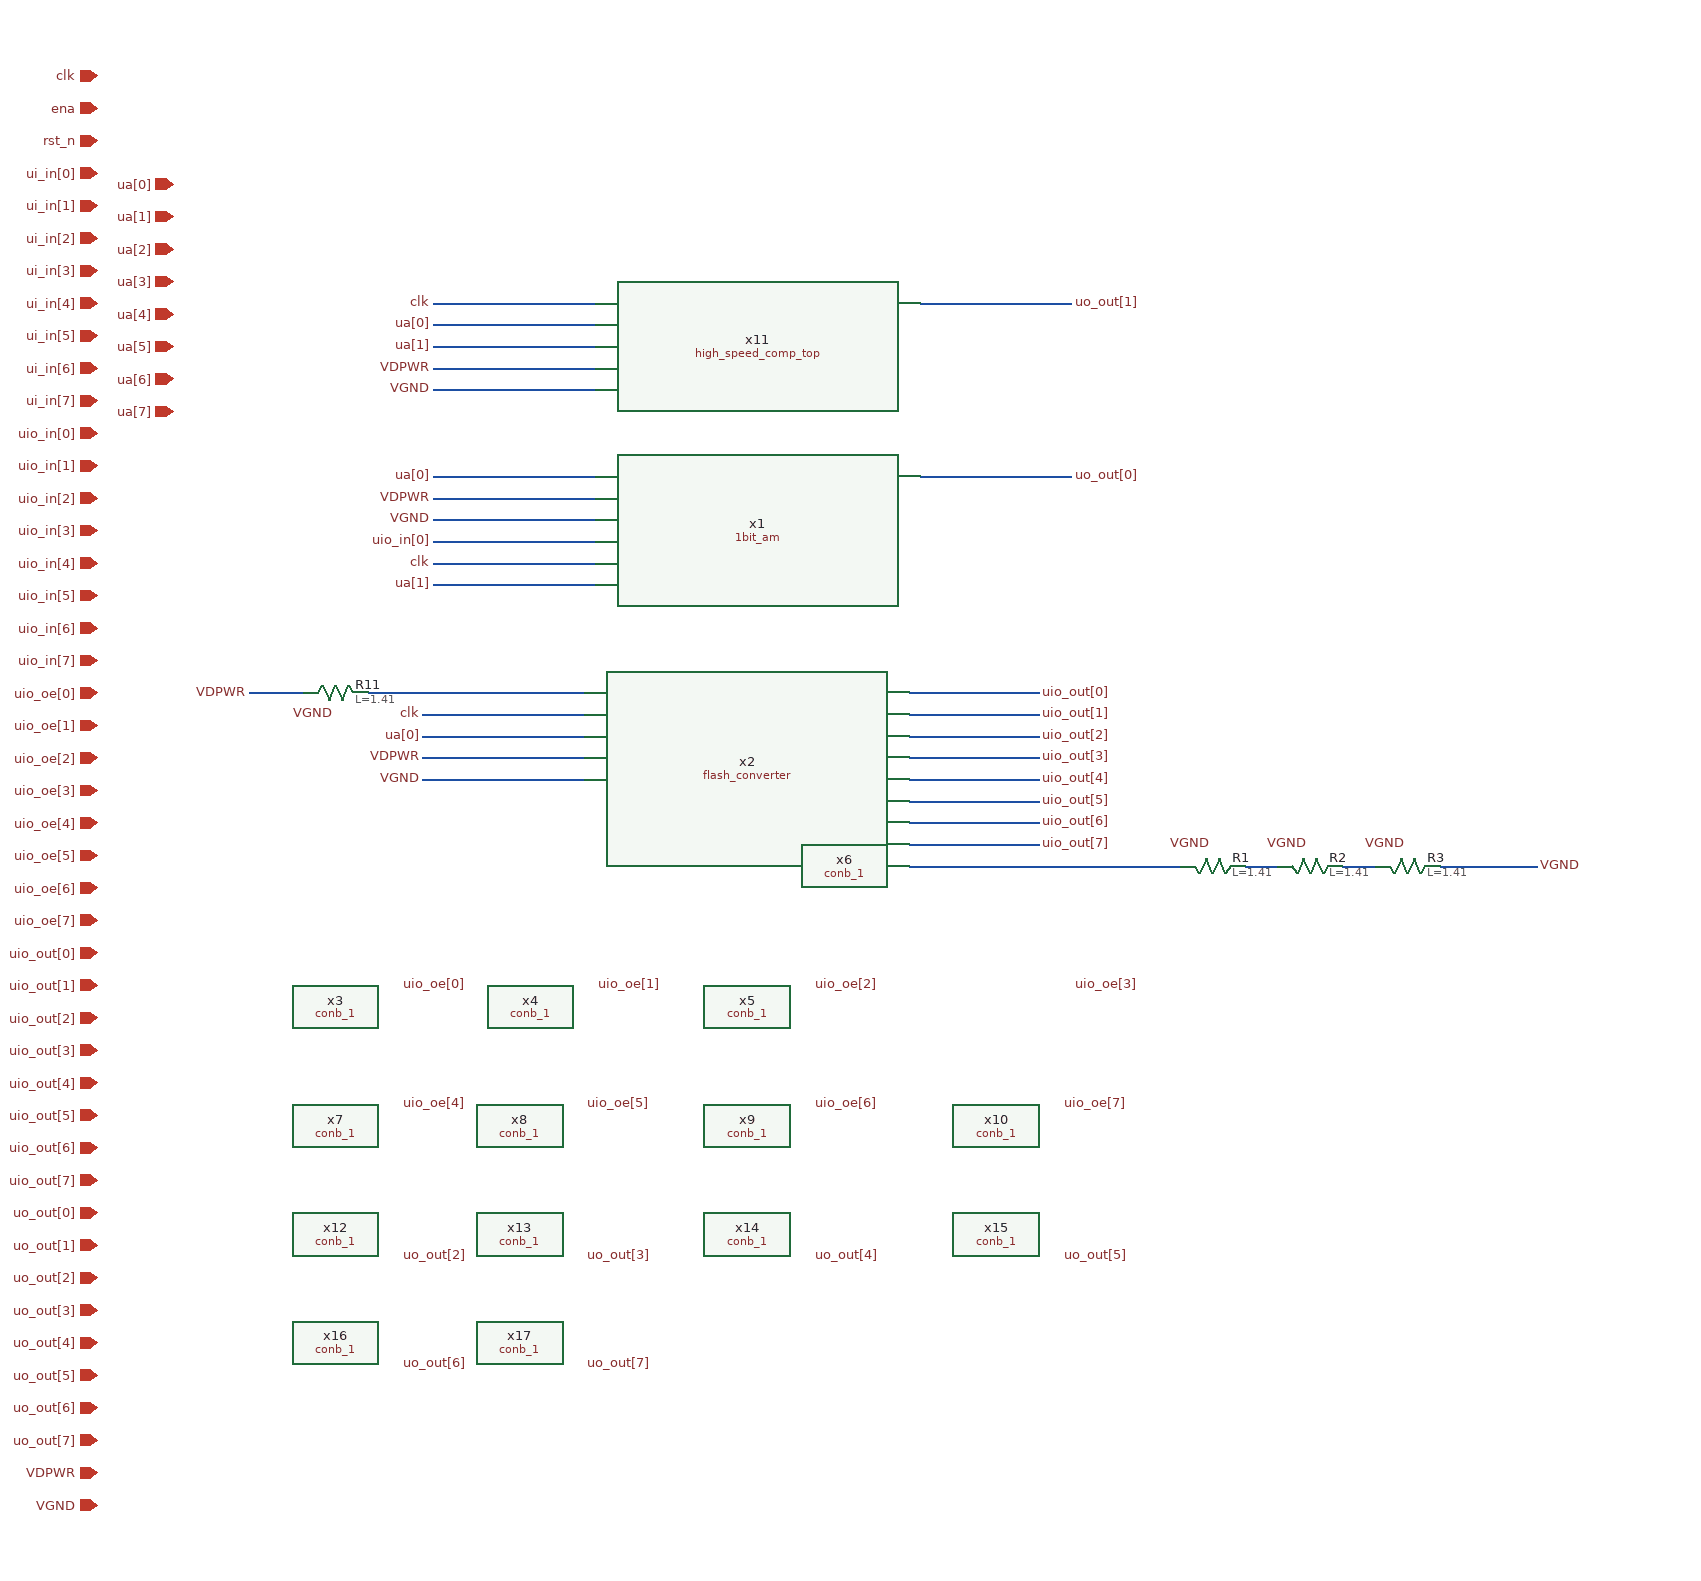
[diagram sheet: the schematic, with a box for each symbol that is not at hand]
v {xschem version=3.4.4 file_version=1.2
}
G {}
K {}
V {}
S {}
E {}
N 160 370 310 370 {
lab=clk}
N 150 510 300 510 {
lab=clk}
N 600 490 720 490 {
lab=uio_out[0]}
N 600 510 720 510 {
lab=uio_out[1]}
N 600 530 720 530 {
lab=uio_out[2]}
N 600 550 720 550 {
lab=uio_out[3]}
N 600 570 720 570 {
lab=uio_out[4]}
N 600 590 720 590 {
lab=uio_out[5]}
N 600 610 720 610 {
lab=uio_out[6]}
N 600 630 720 630 {
lab=uio_out[7]}
N 160 310 310 310 {
lab=VDPWR}
N 160 330 310 330 {
lab=VGND}
N 160 350 310 350 {
lab=uio_in[0]}
N 160 290 310 290 {
lab=ua[0]}
N 160 390 310 390 {
lab=ua[1]}
N 150 550 300 550 {
lab=VDPWR}
N 150 570 300 570 {
lab=VGND}
N 150 530 300 530 {
lab=ua[0]}
N 610 290 750 290 {
lab=uo_out[0]}
N 160 150 310 150 {
lab=ua[0]}
N 160 170 310 170 {
lab=ua[1]}
N 160 190 310 190 {
lab=VDPWR}
N 160 210 310 210 {
lab=VGND}
N 160 130 310 130 {
lab=clk}
N 610 130 750 130 {
lab=uo_out[1]}
N 600 650 850 650 {
lab=#net1}
N 910 650 940 650 {
lab=#net2}
N 1000 650 1030 650 {
lab=#net3}
N 1090 650 1180 650 {
lab=#net4}
N 100 490 300 490 {
lab=#net5}
N -10 490 40 490 {
lab=VDPWR}
C {ipin.sym} -150 -80 0 0 {name=p1 lab=clk}
C {ipin.sym} -150 -50 0 0 {name=p2 lab=ena}
C {ipin.sym} -150 -20 0 0 {name=p3 lab=rst_n}
C {ipin.sym} -80 20 0 0 {name=p4 lab=ua[0]}
C {ipin.sym} -80 50 0 0 {name=p5 lab=ua[1]}
C {ipin.sym} -80 80 0 0 {name=p6 lab=ua[2]}
C {ipin.sym} -80 110 0 0 {name=p7 lab=ua[3]}
C {ipin.sym} -80 140 0 0 {name=p8 lab=ua[4]}
C {ipin.sym} -80 170 0 0 {name=p9 lab=ua[5]}
C {ipin.sym} -80 200 0 0 {name=p10 lab=ua[6]}
C {ipin.sym} -80 230 0 0 {name=p11 lab=ua[7]}
C {ipin.sym} -150 10 0 0 {name=p12 lab=ui_in[0]}
C {ipin.sym} -150 40 0 0 {name=p13 lab=ui_in[1]}
C {ipin.sym} -150 70 0 0 {name=p14 lab=ui_in[2]}
C {ipin.sym} -150 100 0 0 {name=p15 lab=ui_in[3]}
C {ipin.sym} -150 130 0 0 {name=p16 lab=ui_in[4]}
C {ipin.sym} -150 160 0 0 {name=p17 lab=ui_in[5]}
C {ipin.sym} -150 190 0 0 {name=p18 lab=ui_in[6]}
C {ipin.sym} -150 220 0 0 {name=p19 lab=ui_in[7]}
C {ipin.sym} -150 250 0 0 {name=p20 lab=uio_in[0]}
C {ipin.sym} -150 280 0 0 {name=p21 lab=uio_in[1]}
C {ipin.sym} -150 310 0 0 {name=p22 lab=uio_in[2]}
C {ipin.sym} -150 340 0 0 {name=p23 lab=uio_in[3]}
C {ipin.sym} -150 370 0 0 {name=p24 lab=uio_in[4]}
C {ipin.sym} -150 400 0 0 {name=p25 lab=uio_in[5]}
C {ipin.sym} -150 430 0 0 {name=p26 lab=uio_in[6]}
C {ipin.sym} -150 460 0 0 {name=p27 lab=uio_in[7]}
C {ipin.sym} -150 490 0 0 {name=p28 lab=uio_oe[0]}
C {ipin.sym} -150 520 0 0 {name=p29 lab=uio_oe[1]}
C {ipin.sym} -150 550 0 0 {name=p30 lab=uio_oe[2]}
C {ipin.sym} -150 580 0 0 {name=p31 lab=uio_oe[3]}
C {ipin.sym} -150 610 0 0 {name=p32 lab=uio_oe[4]}
C {ipin.sym} -150 640 0 0 {name=p33 lab=uio_oe[5]}
C {ipin.sym} -150 670 0 0 {name=p34 lab=uio_oe[6]}
C {ipin.sym} -150 700 0 0 {name=p35 lab=uio_oe[7]}
C {ipin.sym} -150 730 0 0 {name=p36 lab=uio_out[0]}
C {ipin.sym} -150 760 0 0 {name=p37 lab=uio_out[1]}
C {ipin.sym} -150 790 0 0 {name=p38 lab=uio_out[2]}
C {ipin.sym} -150 820 0 0 {name=p39 lab=uio_out[3]}
C {ipin.sym} -150 850 0 0 {name=p40 lab=uio_out[4]}
C {ipin.sym} -150 880 0 0 {name=p41 lab=uio_out[5]}
C {ipin.sym} -150 910 0 0 {name=p42 lab=uio_out[6]}
C {ipin.sym} -150 940 0 0 {name=p43 lab=uio_out[7]}
C {ipin.sym} -150 970 0 0 {name=p44 lab=uo_out[0]}
C {ipin.sym} -150 1000 0 0 {name=p45 lab=uo_out[1]}
C {ipin.sym} -150 1030 0 0 {name=p46 lab=uo_out[2]}
C {ipin.sym} -150 1060 0 0 {name=p47 lab=uo_out[3]}
C {ipin.sym} -150 1090 0 0 {name=p48 lab=uo_out[4]}
C {ipin.sym} -150 1120 0 0 {name=p49 lab=uo_out[5]}
C {ipin.sym} -150 1150 0 0 {name=p50 lab=uo_out[6]}
C {ipin.sym} -150 1180 0 0 {name=p51 lab=uo_out[7]}
C {ipin.sym} -150 1210 0 0 {name=p52 lab=VDPWR}
C {ipin.sym} -150 1240 0 0 {name=p53 lab=VGND}
C {1bit_am.sym} 460 340 0 0 {name=x1}
C {flash_converter.sym} 450 570 0 0 {name=x2}
C {lab_pin.sym} 160 370 0 0 {name=p54 sig_type=std_logic lab=clk}
C {lab_pin.sym} 150 510 0 0 {name=p55 sig_type=std_logic lab=clk}
C {lab_pin.sym} 720 490 2 0 {name=p56 sig_type=std_logic lab=uio_out[0]}
C {lab_pin.sym} 720 510 2 0 {name=p57 sig_type=std_logic lab=uio_out[1]}
C {lab_pin.sym} 720 530 2 0 {name=p58 sig_type=std_logic lab=uio_out[2]}
C {lab_pin.sym} 720 550 2 0 {name=p59 sig_type=std_logic lab=uio_out[3]}
C {lab_pin.sym} 720 570 2 0 {name=p60 sig_type=std_logic lab=uio_out[4]}
C {lab_pin.sym} 720 590 2 0 {name=p61 sig_type=std_logic lab=uio_out[5]}
C {lab_pin.sym} 720 610 2 0 {name=p62 sig_type=std_logic lab=uio_out[6]}
C {lab_pin.sym} 720 630 2 0 {name=p63 sig_type=std_logic lab=uio_out[7]}
C {sky130_stdcells/conb_1.sym} 70 780 0 0 {name=x3 VGND=VGND VNB=VNB VPB=VPB VPWR=VPWR prefix=sky130_fd_sc_hd__ }
C {sky130_stdcells/conb_1.sym} 250 780 0 0 {name=x4 VGND=VGND VNB=VNB VPB=VPB VPWR=VPWR prefix=sky130_fd_sc_hd__ }
C {sky130_stdcells/conb_1.sym} 450 780 0 0 {name=x5 VGND=VGND VNB=VNB VPB=VPB VPWR=VPWR prefix=sky130_fd_sc_hd__ }
C {sky130_stdcells/conb_1.sym} 690 780 0 0 {name=x6 VGND=VGND VNB=VNB VPB=VPB VPWR=VPWR prefix=sky130_fd_sc_hd__ }
C {sky130_stdcells/conb_1.sym} 70 890 0 0 {name=x7 VGND=VGND VNB=VNB VPB=VPB VPWR=VPWR prefix=sky130_fd_sc_hd__ }
C {sky130_stdcells/conb_1.sym} 240 890 0 0 {name=x8 VGND=VGND VNB=VNB VPB=VPB VPWR=VPWR prefix=sky130_fd_sc_hd__ }
C {sky130_stdcells/conb_1.sym} 450 890 0 0 {name=x9 VGND=VGND VNB=VNB VPB=VPB VPWR=VPWR prefix=sky130_fd_sc_hd__ }
C {sky130_stdcells/conb_1.sym} 680 890 0 0 {name=x10 VGND=VGND VNB=VNB VPB=VPB VPWR=VPWR prefix=sky130_fd_sc_hd__ }
C {lab_pin.sym} 160 290 0 0 {name=p64 sig_type=std_logic lab=ua[0]}
C {lab_pin.sym} 160 310 0 0 {name=p65 sig_type=std_logic lab=VDPWR}
C {lab_pin.sym} 160 330 0 0 {name=p66 sig_type=std_logic lab=VGND}
C {lab_pin.sym} 130 760 2 0 {name=p67 sig_type=std_logic lab=uio_oe[0]}
C {lab_pin.sym} 310 760 2 0 {name=p68 sig_type=std_logic lab=uio_oe[1]}
C {lab_pin.sym} 510 760 2 0 {name=p69 sig_type=std_logic lab=uio_oe[2]}
C {lab_pin.sym} 750 760 2 0 {name=p70 sig_type=std_logic lab=uio_oe[3]}
C {lab_pin.sym} 130 870 2 0 {name=p71 sig_type=std_logic lab=uio_oe[4]}
C {lab_pin.sym} 300 870 2 0 {name=p72 sig_type=std_logic lab=uio_oe[5]}
C {lab_pin.sym} 510 870 2 0 {name=p73 sig_type=std_logic lab=uio_oe[6]}
C {lab_pin.sym} 740 870 2 0 {name=p74 sig_type=std_logic lab=uio_oe[7]}
C {lab_pin.sym} 160 390 0 0 {name=p75 sig_type=std_logic lab=ua[1]}
C {lab_pin.sym} 150 550 0 0 {name=p76 sig_type=std_logic lab=VDPWR}
C {lab_pin.sym} 150 570 0 0 {name=p77 sig_type=std_logic lab=VGND}
C {lab_pin.sym} 150 530 0 0 {name=p78 sig_type=std_logic lab=ua[0]}
C {lab_pin.sym} 750 290 2 0 {name=p79 sig_type=std_logic lab=uo_out[0]}
C {high_speed_comp_top.sym} 460 170 0 0 {name=x11}
C {lab_pin.sym} 160 350 0 0 {name=p80 sig_type=std_logic lab=uio_in[0]}
C {lab_pin.sym} 160 150 0 0 {name=p81 sig_type=std_logic lab=ua[0]}
C {lab_pin.sym} 160 170 0 0 {name=p82 sig_type=std_logic lab=ua[1]}
C {lab_pin.sym} 160 190 0 0 {name=p83 sig_type=std_logic lab=VDPWR}
C {lab_pin.sym} 160 210 0 0 {name=p84 sig_type=std_logic lab=VGND}
C {lab_pin.sym} 160 130 0 0 {name=p85 sig_type=std_logic lab=clk}
C {lab_pin.sym} 750 130 2 0 {name=p86 sig_type=std_logic lab=uo_out[1]}
C {sky130_stdcells/conb_1.sym} 70 990 0 0 {name=x12 VGND=VGND VNB=VNB VPB=VPB VPWR=VPWR prefix=sky130_fd_sc_hd__ }
C {sky130_stdcells/conb_1.sym} 240 990 0 0 {name=x13 VGND=VGND VNB=VNB VPB=VPB VPWR=VPWR prefix=sky130_fd_sc_hd__ }
C {sky130_stdcells/conb_1.sym} 450 990 0 0 {name=x14 VGND=VGND VNB=VNB VPB=VPB VPWR=VPWR prefix=sky130_fd_sc_hd__ }
C {sky130_stdcells/conb_1.sym} 680 990 0 0 {name=x15 VGND=VGND VNB=VNB VPB=VPB VPWR=VPWR prefix=sky130_fd_sc_hd__ }
C {lab_pin.sym} 130 1010 2 0 {name=p87 sig_type=std_logic lab=uo_out[2]}
C {lab_pin.sym} 300 1010 2 0 {name=p88 sig_type=std_logic lab=uo_out[3]}
C {lab_pin.sym} 510 1010 2 0 {name=p89 sig_type=std_logic lab=uo_out[4]}
C {lab_pin.sym} 740 1010 2 0 {name=p90 sig_type=std_logic lab=uo_out[5]}
C {sky130_stdcells/conb_1.sym} 70 1090 0 0 {name=x16 VGND=VGND VNB=VNB VPB=VPB VPWR=VPWR prefix=sky130_fd_sc_hd__ }
C {sky130_stdcells/conb_1.sym} 240 1090 0 0 {name=x17 VGND=VGND VNB=VNB VPB=VPB VPWR=VPWR prefix=sky130_fd_sc_hd__ }
C {lab_pin.sym} 130 1110 2 0 {name=p91 sig_type=std_logic lab=uo_out[6]}
C {lab_pin.sym} 300 1110 2 0 {name=p92 sig_type=std_logic lab=uo_out[7]}
C {sky130_fd_pr/res_high_po_1p41.sym} 70 490 3 0 {name=R11
L=1.41
model=res_high_po_1p41
spiceprefix=X
mult=1}
C {sky130_fd_pr/res_high_po_1p41.sym} 880 650 1 0 {name=R1
L=1.41
model=res_high_po_1p41
spiceprefix=X
mult=1}
C {sky130_fd_pr/res_high_po_1p41.sym} 970 650 1 0 {name=R2
L=1.41
model=res_high_po_1p41
spiceprefix=X
mult=1}
C {sky130_fd_pr/res_high_po_1p41.sym} 1060 650 1 0 {name=R3
L=1.41
model=res_high_po_1p41
spiceprefix=X
mult=1}
C {lab_pin.sym} -10 490 0 0 {name=p93 sig_type=std_logic lab=VDPWR}
C {lab_pin.sym} 70 510 0 0 {name=p94 sig_type=std_logic lab=VGND}
C {lab_pin.sym} 880 630 0 0 {name=p95 sig_type=std_logic lab=VGND}
C {lab_pin.sym} 970 630 0 0 {name=p96 sig_type=std_logic lab=VGND}
C {lab_pin.sym} 1060 630 0 0 {name=p97 sig_type=std_logic lab=VGND}
C {lab_pin.sym} 1180 650 2 0 {name=p98 sig_type=std_logic lab=VGND}
